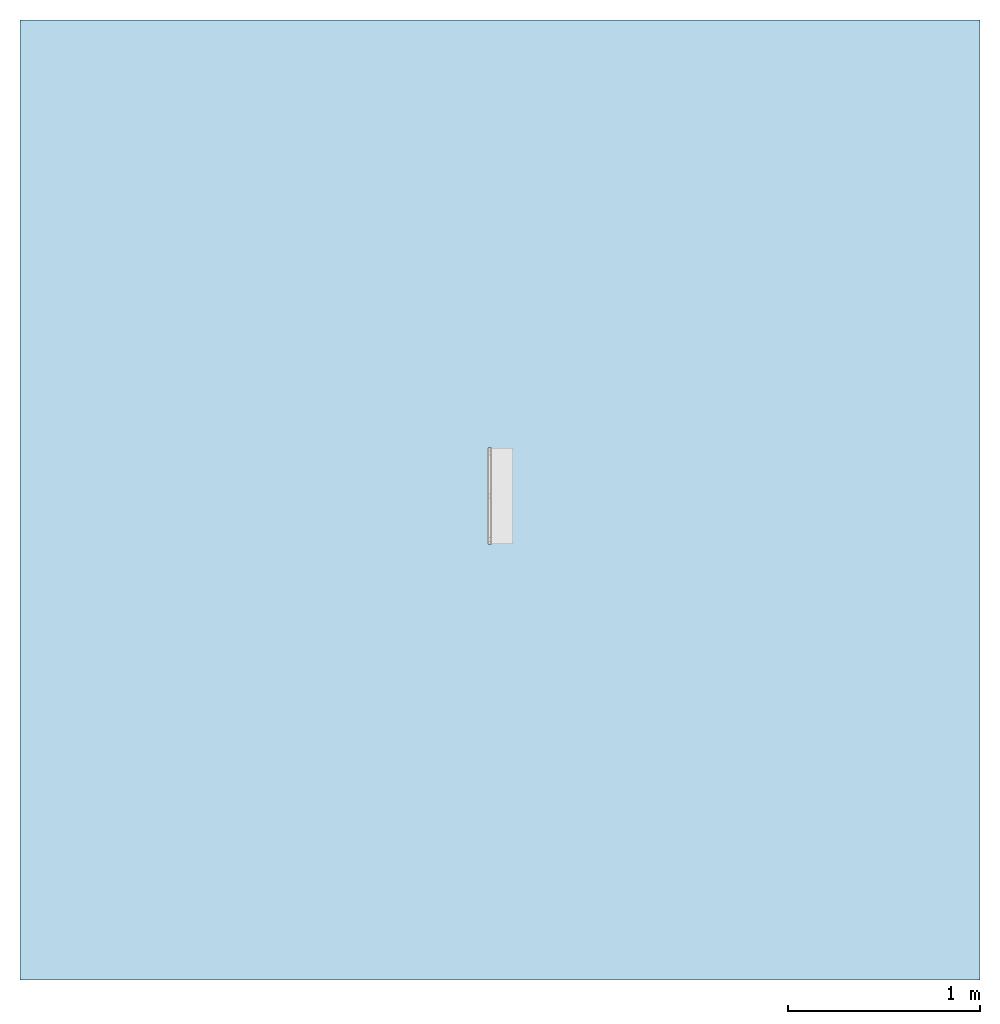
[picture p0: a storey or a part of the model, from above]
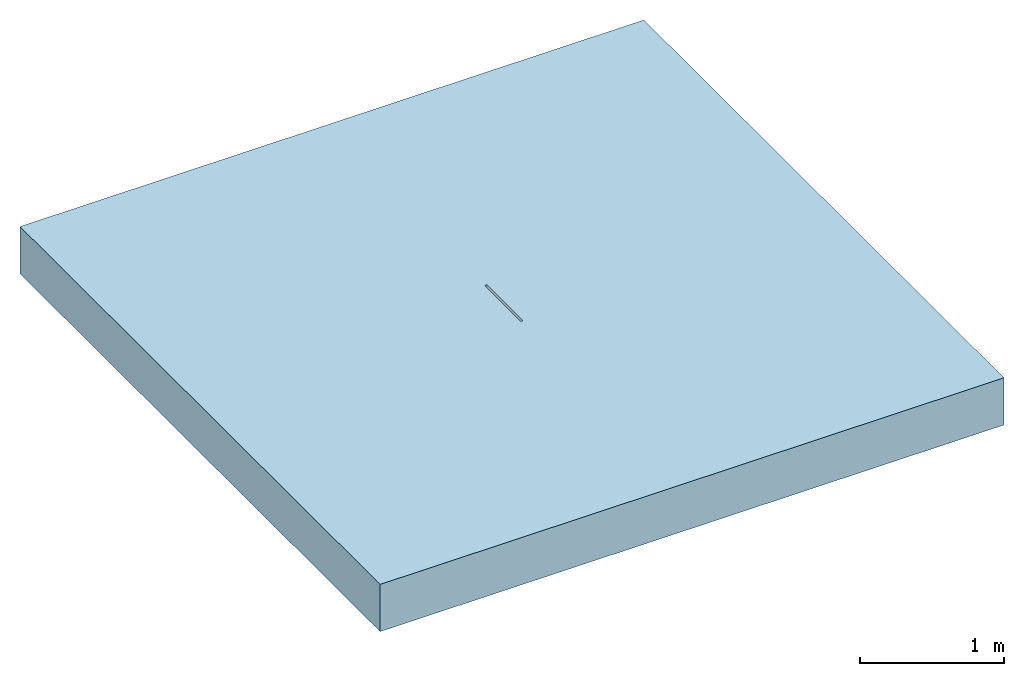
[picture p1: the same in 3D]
Properties of the parts of a building model (IFC2X3)

# File
Description: ViewDefinition [CoordinationView]
File name: 24101.ifc
Time: 2013-10-30T12:02:32
Written by: Autodesk Revit 2013
Made in: 20120221_2030(x64)

# IfcProject, Project Number
LongName: Project Name; Phase: Project Status

# IfcSite, Default
RefLatitude: 42, 21, 30, 344238; RefLongitude: -71, -3, -35, -194702; RefElevation: 0 mm

# IfcBuilding
Pset_BuildingCommon - NumberOfStoreys: 1
Other - Project Number: Project Number; Project Status: Project Status; Client Name: Owner; Project Name: Project Name; Project Issue Date: Issue Date; Project Address: ## Street City, State Zip

# IfcBuildingStorey, Level 1
LongName: Level 1; Elevation: 0 mm
Constraints - Elevation Base: 0; Elevation: 0 mm
Graphics - Symbol at End 1 Default: no; Line Pattern: Center; Color: 0; Symbol at End 2 Default: yes; Symbol: M_Level Head - Circle: M_Level Head - Circle; Line Weight: 1
Identity Data - Name: Level 1; Structural: no; Building Story: yes
Dimensions - Computation Height: 0 mm

# IfcBuildingElementProxy: 24101 - No 10.1J Constant Depth Channel - 500mm LG -Invert Depth 180mm, Civil-Drainage-Channel-ACO-MultiDrain-M100DS-Brickslot-Channel-System:24101 - No 10.1J Constant Depth Channel - 500mm LG -Invert Depth 180mm:24101 - No 10.1J Constant Depth Channel - 500mm LG -Invert Depth 180mm:196059
In: Level 1
Material: Stainless Steel (F), Vienite® Synthetic Resin Concrete
Dimensions - Volume: 4879234 mm3; Brickslot Access Unit Void Depth: -6500 mm; Custom_Void_length: 0 mm; Brickslot Void Length: 500 mm; Length: 1000 mm; FloorCut_Length: -500 mm; EndCap Position: 500 mm; Brickslot Void Depth: 0 mm; Brickslot Access Unit Void Bottom Depth: -6605 mm; EndCap_Height: 200 mm; InvDepth: 130 mm; ShallowOverallDepth: 75 mm; Brickslot Access Unit Floor Cut Length: 500 mm; Depth: 200 mm; GratingLength: -1000 mm; FloorCut_Width: 135 mm; Floor Cut Gap: 105 mm; FloorCut_Depth: 200 mm; Length Drain: -500 mm; ShallowInvDepth: 55 mm
Construction - 23404_Universal Endcap (Male End): no; 23404_Universal Endcap (Female End): no; 23475_Load Class C250 & D400_Brickslot Grating_Stainless Steel_1000mm Long: no; 23476_Load Class C250 & D400_Brickslot Grating_Stainless Steel_500mm Long: yes; 23477_Load Class C250 & D400_Brickslot_Access Unit_Stainless Steel_500mm Long: no; 23410_Sump Unit: no; Constant Depth Junction Channel: yes; Constant Depth Channel: no; Shallow Depth Channel with seal: no; Shallow Depth Channel: no
Phasing - Phase Created: New Construction
Constraints - Moves With Nearby Elements: no; Level: Level: Level 1
Pset_BuildingElementProxyCommon - Reference: 24101 - No 10.1J Constant Depth Channel - 500mm LG -Invert Depth 180mm
Identity Data - Product Code: 24101; Model Description: Channel drainage system; Watermark 1: This file is the property of ACO Technologies PLC; URL: www.aco.co.uk; Installation guidelines: http://www.aco.co.uk/download.php?id=173; e-mail Sales: customersupport@aco.co.uk; Price: POA - contact ACO; Telephone: +44 (0)1462 816666; Product brochure: http://www.aco.co.uk/download.php?id=173; Assembly Description: Rain Water Drainage; Address: ACO Business Park, Hitchin Road, Shefford, Bedfordshire, United Kingdom SG17 5TE; OmniClass Title: Rainwater Removal; Fax: +44 (0)1462 815895; Type Comments: ACO MultiDrain M100DS 10.1J Constant Depth Junction Channel 500mm Long; Maintenance guidelines: http://www.aco.co.uk/download.php?id=173; OmniClass Number: 23.70.50.24; Manufacturer: ACO Technologies plc - ACO Water Management Division; Cost: 0; e-mail Technical: technical@aco.co.uk; Model: ACO MultiDrain MDS Brickslot- M100DS; Watermark 2: This file is water marked and users are prohibited to reproduce, adapt, distribute this information; Product Page URL: http://www.aco.co.uk/product_detail.php?id=58; Assembly Code: D2040; Watermarked By: www.aco.co.uk; Watermarked With: BIM Manager Premium Suite
Data - Product Weight: 10.2 Kg; Invert Depth: 180mm; Product Standard: BS EN 1433:2002, CE marked; Load Class: A 15 - D 400; Concrete Surround Volume - Load Class B 125 - C 250 - Concrete Pavement: 0.13m³/m; ACO Hydraulic Design Software: http://www.acodesign.co.uk; Concrete Surround Volume - Load Class A 15 - Concrete Pavement: 0.08m³/m; Hydraulic Performance: http://www.aco.co.uk/download.php?id=173; Installation - Concrete Grade: Refer to brochure; Product Dimensions: 500mm x 135mm x 200mm (LxWxH); Pre-formed Outlet Ø: N/A; Channel C.S.A: 0.013m²; Concrete Surround Volume - Load Class D 400 - Concrete Pavement: 0.19m³/m
Green Building Properties - Edge Rail Recycled Material Content: Between 40% - 90%; Channel Recyclable: Fully recyclable; Edge Rail Recyclable: Fully recyclable; Channel Recycled Material Content: 20% minimum
General - SerialNumber: 0; TagNumber: 0
Model Properties - Brickslot Grating Product code 23476: Load Class C250/D400 - Brickslot Stainless Steel - 500mm long x 105mm high -10mm Slot- Intake area - 1000mm²/m - 3.3 Kg; Brickslot Access Unit Product code 23477: Load Class C250/D400 - Brickslot Access Unit Stainless Steel - 500mm long x 105mm high -10mm Slot- Intake area - 1000mm²/m - 6.4 Kg; Brickslot Grating Product code 23475: N/A; End Cap Product code 23404: No 306 Universl End Cap - 135mm wide x 300mm long - Spigot Ø110mm x 50mm long - Silver - Polypropylene - 0.16kg
Other - Created By: www.aco.co.uk; Revision: 1
Materials and Finishes - Channel Colour: Brown; Channel Material: Vienite® Synthetic Resin Concrete; Edge Rail Colour: Self; Edge Rail Material: Stainless Steel Grade 304

# IfcOpeningElement: Recess (2)
In: Level 1
Phasing - Phase Created: New Construction
Structural - Structural: no; Enable Analytical Model: no
Dimensions - Area: 25000000 mm2; Perimeter: 20000 mm; Volume: 9985555000 mm3; Thickness: 400 mm
Constraints - Height Offset From Level: 0 mm; Room Bounding: yes; Related to Mass: no; Level: Level: Level 1
Materials and Finishes - Structural Material: Earth
Graphics - Coarse Scale Fill Color: 0
Analytical Properties - Thermal mass: 543920; Absorptance: 0.1; Thermal Resistance (R): 0.477897; Heat Transfer Coefficient (U): 2.0925; Roughness: 1
Construction - Function: 0; Default Thickness: 400 mm

# IfcSlab: Floor:Generic Floor - 400mm, Floor:Generic Floor - 400mm:193825
In: Level 1
PredefinedType: FLOOR; Material: Earth 400 mm
Phasing - Phase Created: New Construction
Structural - Structural: no; Enable Analytical Model: no
Dimensions - Area: 25000000 mm2; Perimeter: 20000 mm; Volume: 9985555000 mm3; Thickness: 400 mm
Constraints - Height Offset From Level: 0 mm; Room Bounding: yes; Related to Mass: no; Level: Level: Level 1
Pset_SlabCommon - Reference: Generic Floor - 400mm; IsExternal: no; LoadBearing: yes
Materials and Finishes - Structural Material: Earth
Graphics - Coarse Scale Fill Color: 0
Analytical Properties - Thermal mass: 543920; Absorptance: 0.1; Thermal Resistance (R): 0.477897; Heat Transfer Coefficient (U): 2.0925; Roughness: 1
Construction - Function: 0; Default Thickness: 400 mm
